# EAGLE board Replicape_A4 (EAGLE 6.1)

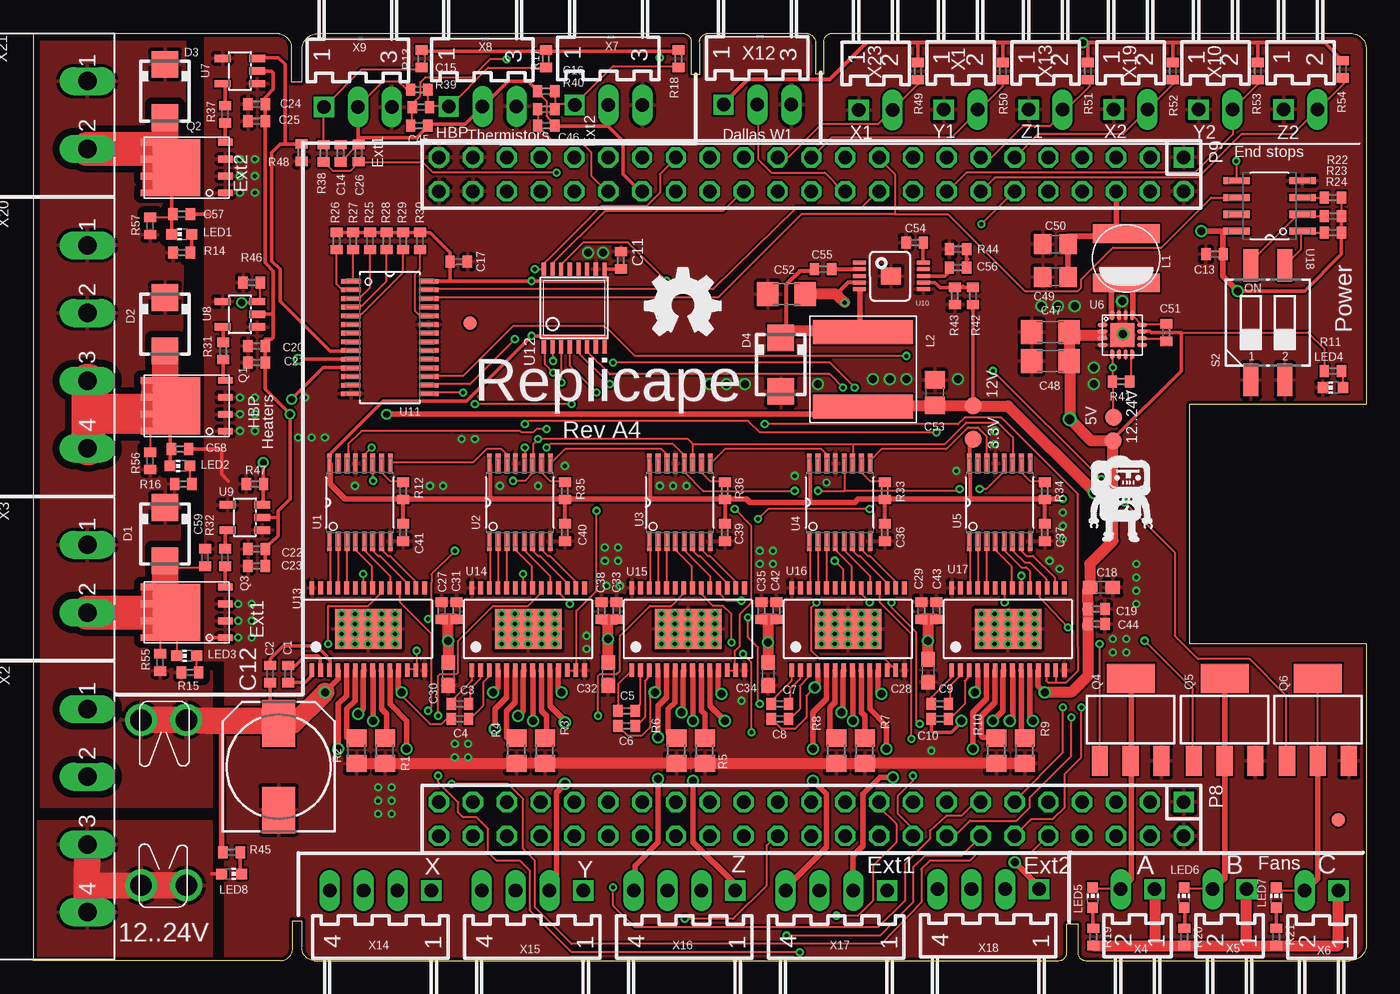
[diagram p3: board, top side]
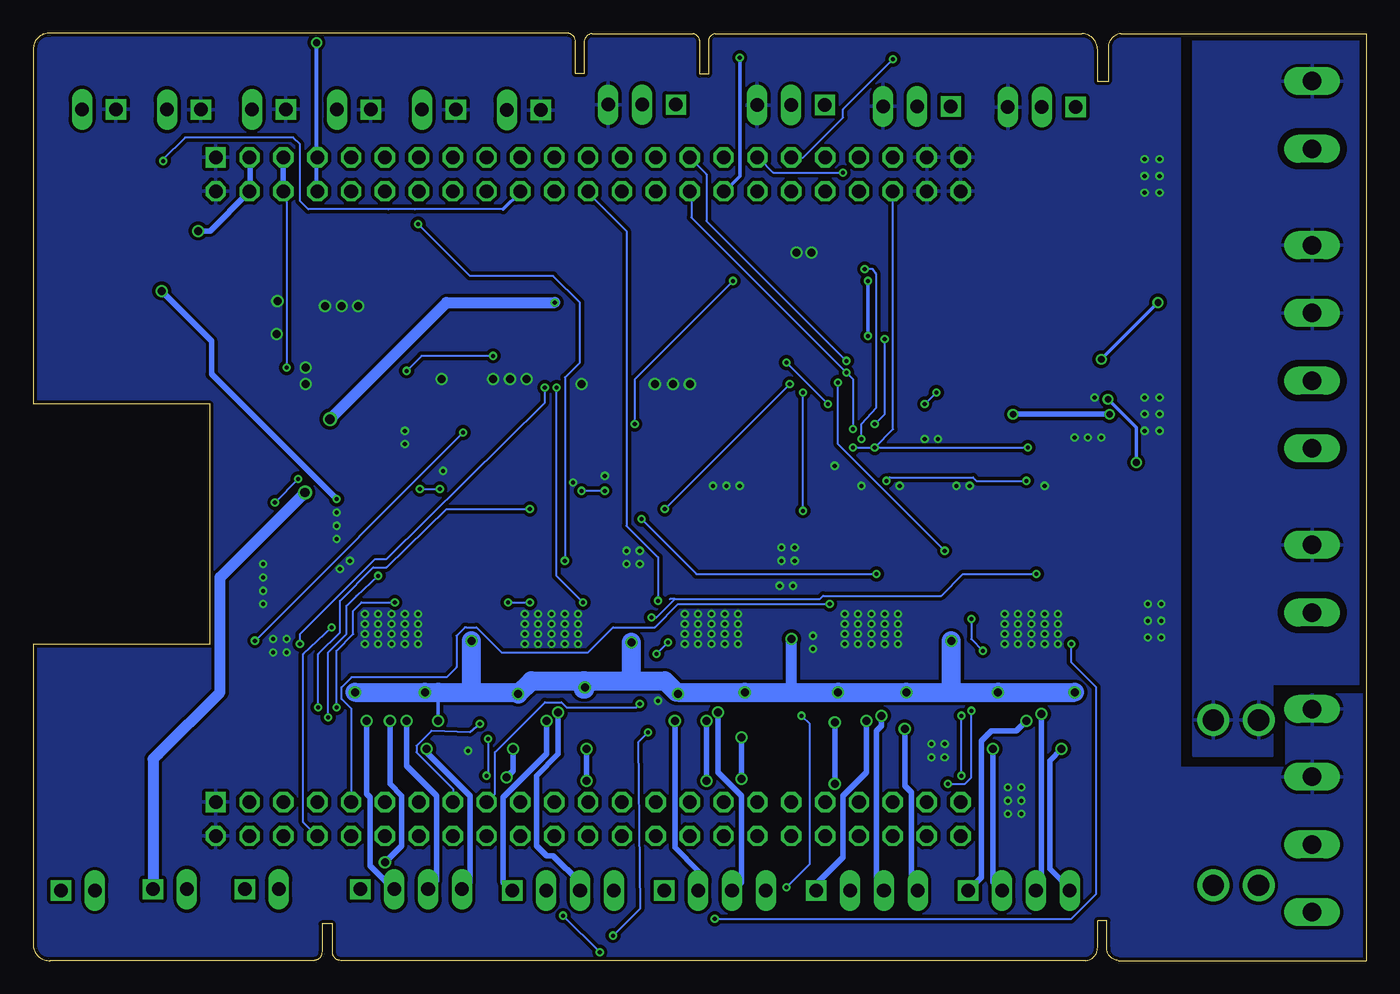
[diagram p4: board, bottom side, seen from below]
Size 100 x 69.58 mm. Coordinates in mm from the lower left corner, seen from the top.
Outline: 19.45,3 20.15,3 20.15,1.05 arc90 21.05,0 76.95,0 arc90 77.55,0.65 77.55,2.75 78.35,2.75 78.35,0.65 arc90 78.95,0 98.75,0 arc90 100,1.1 100,23.75 86.75,23.75 86.75,41.75 100,41.75 100,68.5 arc90 98.75,69.58 59.88,69.58 arc90 59.33,68.9 59.33,66.55 58.67,66.55 58.67,68.85 arc90 58.08,69.55 50.5,69.55 arc90 50,68.85 50,66.5 49.35,66.5 49.35,68.85 arc90 48.85,69.55 21.35,69.55 arc90 20.15,68.35 20.15,65.95 19.35,65.95 19.35,68.35 arc90 18.43,69.55 0,69.55 0,0 18.6,0 arc90 19.45,0.95 19.45,3
Copper layers (1*16): Top 0.035mm / dielectric 1.5mm / Bottom 0.035mm
Design rules: minimum track width 6mil, minimum drill 12mil, track to track 6mil, track to pad 6mil, pad to pad 6mil, via to via 6mil, smd to smd 0mil, copper to edge 10mil, drill to drill 10mil, minimum pad ring 10mil, minimum via ring 6mil, stop-mask expansion 2mil, vias tented up to drill 100mil, thermal gap 10mil
Net classes: 1 power: width 1.27 mm

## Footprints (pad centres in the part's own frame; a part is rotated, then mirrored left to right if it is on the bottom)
B1,27 = smd 1.27 x 1.27: TP 0,0
C0402 = smd 0.7 x 0.9: 1 -0.65,0; 2 0.65,0
140CLH-0810 = smd 3.5 x 2.5: + 3.25,0; - -3.25,0
C0603 = smd 1.1 x 1: 1 -0.85,0; 2 0.85,0
C1206 = smd 1.6 x 1.8: 1 -1.4,0; 2 1.4,0
C0805 = smd 1.3 x 1.5: 1 -0.95,0; 2 0.95,0
SMA = smd 2 x 2: A 2,0; C -2,0
3557 = drill 1.6: 1 -6.2,1.7; 2 -6.2,-1.7; 3 6.2,-1.7; 4 6.2,1.7
FIDUCIAL-1X2.5 = smd 1 x 1: 1 0,0
VLC5020 = smd 5 x 1.4: 1 0,1.85; 2 0,-1.85
NR8040T330 = smd 1.8 x 7.5: P$1 2.8,0; P$2 -2.8,0
CHIP-LED0603 = smd 0.8 x 0.8: A 0,-0.75; C 0,0.75
DIL-100-2X23 = drill 1.016 square: 1 -27.94,-1.27 | drill 1.016 octagon: 2 -27.94,1.27; 3 -25.4,-1.27; 4 -25.4,1.27; 5 -22.86,-1.27; 6 -22.86,1.27; 7 -20.32,-1.27; 8 -20.32,1.27; 9 -17.78,-1.27; 10 -17.78,1.27; 11 -15.24,-1.27; 12 -15.24,1.27; 13 -12.7,-1.27; 14 -12.7,1.27; 15 -10.16,-1.27; 16 -10.16,1.27; 17 -7.62,-1.27; 18 -7.62,1.27; 19 -5.08,-1.27; 20 -5.08,1.27; 21 -2.54,-1.27; 22 -2.54,1.27; 23 0,-1.27; 24 0,1.27; 25 2.54,-1.27; 26 2.54,1.27; 27 5.08,-1.27; 28 5.08,1.27; 29 7.62,-1.27; 30 7.62,1.27; 31 10.16,-1.27; 32 10.16,1.27; 33 12.7,-1.27; 34 12.7,1.27; 35 15.24,-1.27; 36 15.24,1.27; 37 17.78,-1.27; 38 17.78,1.27; 39 20.32,-1.27; 40 20.32,1.27; 41 22.86,-1.27; 42 22.86,1.27; 43 25.4,-1.27; 44 25.4,1.27; 45 27.94,-1.27; 46 27.94,1.27
8-DFN-EP-(5X6) = smd 1.1 x 0.5: 1 -2.9,1.905; 2 -2.9,0.635; 3 -2.9,-0.635; 4 -2.9,-1.905; 5 2.9,-1.905; 6 2.9,-0.635; 7 2.9,0.635; 8 2.9,1.905 | smd 3.5 x 4.3: TH 0.75,0
SOT223 = smd 1.219 x 2.235: 1 -2.311,-3.099; 2 0,-3.099; 3 2.311,-3.099 | smd 3.6 x 2.2: 4 0,3.099
R0805 = smd 1.3 x 1.5: 1 -0.95,0; 2 0.95,0
R0402 = smd 0.7 x 0.9: 1 -0.65,0; 2 0.65,0
CTS-219-02 = smd 1.13 x 2.44: 1 -1.27,-4.3; 2 1.27,-4.3; 3 1.27,4.3; 4 -1.27,4.3
SOP65P640X120-16N = smd 1.473 x 0.356: 1 -2.921,2.286; 2 -2.921,1.626; 3 -2.921,0.965; 4 -2.921,0.33; 5 -2.921,-0.33; 6 -2.921,-0.965; 7 -2.921,-1.626; 8 -2.921,-2.286; 9 2.921,-2.286; 10 2.921,-1.626; 11 2.921,-0.965; 12 2.921,-0.33; 13 2.921,0.33; 14 2.921,0.965; 15 2.921,1.626; 16 2.921,2.286
QFN-16 = smd 0.75 x 0.3: 1 -1.475,0.75; 2 -1.475,0.25; 3 -1.475,-0.25; 4 -1.475,-0.75; 9 1.475,-0.75; 10 1.475,-0.25; 11 1.475,0.25; 12 1.475,0.75 | smd 0.3 x 0.75: 5 -0.75,-1.475; 6 -0.25,-1.475; 7 0.25,-1.475; 8 0.75,-1.475; 13 0.75,1.475; 14 0.25,1.475; 15 -0.25,1.475; 16 -0.75,1.475 | smd 1.8 x 1.8: P$17 0,0
SOT23-5L = smd 0.55 x 1.2: 1 -0.95,-1.3; 2 0,-1.3; 3 0.95,-1.3; 4 0.95,1.3; 5 -0.95,1.3
MSOP10 = smd 0.3 x 1: 1 -1,-2.4; 2 -0.5,-2.4; 3 0.005,-2.4; 4 0.5,-2.4; 5 1,-2.4; 6 1,2.4; 7 0.5,2.4; 8 0.005,2.4; 9 -0.5,2.4; 10 -1,2.4 | smd 1.3 x 1.5: EP 0.02,-0.04
SOP65P640X110-28N = smd 1.473 x 0.356: 1 -2.921,4.216; 2 -2.921,3.581; 3 -2.921,2.921; 4 -2.921,2.286; 5 -2.921,1.626; 6 -2.921,0.965; 7 -2.921,0.33; 8 -2.921,-0.33; 9 -2.921,-0.965; 10 -2.921,-1.626; 11 -2.921,-2.286; 12 -2.921,-2.921; 13 -2.921,-3.581; 14 -2.921,-4.216; 15 2.921,-4.216; 16 2.921,-3.581; 17 2.921,-2.921; 18 2.921,-2.286; 19 2.921,-1.626; 20 2.921,-0.965; 21 2.921,-0.33; 22 2.921,0.33; 23 2.921,0.965; 24 2.921,1.626; 25 2.921,2.286; 26 2.921,2.921; 27 2.921,3.581; 28 2.921,4.216
TSSOP-16 = smd 0.305 x 0.991: 1 -2.275,-2.918; 2 -1.625,-2.918; 3 -0.975,-2.918; 4 -0.325,-2.918; 5 0.325,-2.918; 6 0.975,-2.918; 7 1.625,-2.918; 8 2.275,-2.918; 9 2.275,2.918; 10 1.625,2.918; 11 0.975,2.918; 12 0.325,2.918; 13 -0.325,2.918; 14 -0.975,2.918; 15 -1.625,2.918; 16 -2.275,2.918
TSSOP-28 = smd 0.35 x 1: 1 -4.225,-3.087; 2 -3.575,-3.087; 3 -2.925,-3.087; 4 -2.275,-3.087; 5 -1.625,-3.087; 6 -0.975,-3.087; 7 -0.325,-3.087; 8 0.325,-3.087; 9 0.975,-3.087; 10 1.625,-3.087; 11 2.275,-3.087; 12 2.925,-3.087; 13 3.575,-3.087; 14 4.225,-3.087; 15 4.225,3.087; 16 3.575,3.087; 17 2.925,3.087; 18 2.275,3.087; 19 1.625,3.087; 20 0.975,3.087; 21 0.325,3.087; 22 -0.325,3.087; 23 -0.975,3.087; 24 -1.625,3.087; 25 -2.275,3.087; 26 -2.925,3.087; 27 -3.575,3.087; 28 -4.225,3.087 | smd 5 x 3: EXP 0,0
SOIC127P600X175-8N = smd 1.981 x 0.533: 1 -2.464,1.905; 2 -2.464,0.635; 3 -2.464,-0.635; 4 -2.464,-1.905; 5 2.464,-1.905; 6 2.464,-0.635; 7 2.464,0.635; 8 2.464,1.905
7395-02 = drill 1.016 square: 1 1.27,0 | drill 1.016 long: 2 -1.27,0
MSTBA4 = drill 1.397 long: 1 -7.62,5.08; 2 -2.54,5.08; 3 2.54,5.08; 4 7.62,5.08
MSTBA2 = drill 1.397 long: 1 -2.54,5.08; 2 2.54,5.08
7395-03 = drill 1.016 square: 1 2.54,0 | drill 1.016 long: 2 0,0; 3 -2.54,0
7395-04 = drill 1.016 square: 1 3.81,0 | drill 1.016 long: 2 1.27,0; 3 -1.27,0; 4 -3.81,0

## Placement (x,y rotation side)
3.3V  TPB1,27  [B1,27]  70.5,39.13 0 top
5V  TPB1,27  [B1,27]  81.05,40.75 0 top
12..24V  TPB1,27  [B1,27]  81,39 0 top
12V  TPB1,27  [B1,27]  70.5,41.63 0 top
C1  10nF  [C0402]  19.12,21.5 270 top
C2  0.1uF  [C0402]  17.75,21.5 90 top
C3  10nF  [C0402]  32,19.25 180 top
C4  0.1uF  [C0402]  32,18.13 0 top
C5  10nF  [C0402]  44.5,18.75 180 top
C6  0.1uF  [C0402]  44.5,17.63 0 top
C7  10nF  [C0402]  56,19.25 180 top
C8  0.1uF  [C0402]  56,18.13 0 top
C9  10nF  [C0402]  68,19.25 180 top
C10  0.1uF  [C0402]  68,18.13 0 top
C11  0.1uF  [C0402]  44.08,52.55 90 top
C12  100uF  [140CLH-0810]  18.4,14.55 90 top
C13  0.1uF  [C0402]  88.62,53 180 top
C14  0.47uF  [C0402]  23.05,60.58 270 top
C15  0.47uF  [C0402]  28.95,65.35 180 top
C16  0.47uF  [C0402]  38.48,65.23 180 top
C17  0.1uF  [C0402]  31.92,52.43 0 top
C18  4.7uF  [C0603]  80.12,28 0 top
C19  0.1uF  [C0402]  79.75,26.38 0 top
C20  0.1uF  [C0402]  16.75,46.13 180 top
C21  4.7uF  [C0402]  16.75,44.88 180 top
C22  0.1uF  [C0402]  16.75,30.88 180 top
C23  4.7uF  [C0402]  16.75,29.63 180 top
C24  0.1uF  [C0402]  16.75,64.25 180 top
C25  4.7uF  [C0402]  16.75,63 180 top
C26  0.47uF  [C0402]  24.4,60.6 90 top
C27  0.1uF  [C0402]  30.62,26.25 90 top
C28  4.7uF  [C0603]  67.12,21.75 270 top
C29  0.1uF  [C0402]  66.62,26.25 90 top
C30  4.7uF  [C0603]  31.12,21.5 270 top
C31  0.1uF  [C0402]  31.75,26.25 90 top
C32  4.7uF  [C0603]  43.12,21.5 270 top
C33  0.1uF  [C0402]  43.75,26.25 90 top
C34  4.7uF  [C0603]  55.12,21.5 270 top
C35  0.1uF  [C0402]  54.62,26.25 90 top
C36  0.1uF  [C0402]  63.88,32.13 270 top
C37  0.1uF  [C0402]  75.88,32.13 270 top
C38  0.1uF  [C0402]  42.62,26.25 90 top
C39  0.1uF  [C0402]  51.88,32.13 270 top
C40  0.1uF  [C0402]  39.88,32.13 270 top
C41  0.1uF  [C0402]  27.75,32.13 270 top
C42  0.1uF  [C0402]  55.75,26.25 90 top
C43  0.1uF  [C0402]  67.75,26.25 90 top
C44  0.1uF  [C0402]  79.75,25.25 0 top
C45  0.47uF  [C0402]  28.95,62.65 0 top
C46  0.47uF  [C0402]  38.48,62.65 0 top
C47  10uF  [C1206]  76.3,47.18 180 top
C48  10uF  [C1206]  76.3,45 180 top
C49  22uF  [C0805]  76.67,51.3 180 top
C50  22uF  [C0805]  76.67,53.75 180 top
C51  22nF  [C0402]  85,47.13 90 top
C52  10uF  [C1206]  56.5,50 180 top
C53  22uF  [C0805]  67.62,42.63 90 top
C54  10nF  [C0402]  66.12,53.88 180 top
C55  10nF  [C0402]  59.25,51.88 180 top
C56  1nF  [C0402]  69.38,52 0 top
C57  4.7nF  [C0402]  11.12,56 0 top
C58  4.7nF  [C0402]  11,38.38 0 top
C59  4.7nF  [C0402]  12.88,30.25 90 top
D1  MBRA340T3  [SMA]  9.88,32 270 top
D2  MBRA340T3  [SMA]  9.88,47.75 270 top
D3  MBRA340T3  [SMA]  9.88,65.25 270 top
D4  MBRA340T3  [SMA]  56.08,44.73 270 top
F1  3557  [3557]  9.78,11.85 90 top
JP1  FIDUCIAL1X2.5  [FIDUCIAL-1X2.5]  32.77,47.83 0 top
JP2  FIDUCIAL1X2.5  [FIDUCIAL-1X2.5]  97.9,10.55 0 top
L1  4.7uH  [VLC5020]  82,52.7 180 top
L2  33uH  [NR8040T330]  62.25,44.38 270 top
LED1  blue  [CHIP-LED0603]  11.12,54.5 90 top
LED2  blue  [CHIP-LED0603]  11,37.13 90 top
LED3  blue  [CHIP-LED0603]  11.5,22.88 90 top
LED4  blue  [CHIP-LED0603]  97.5,43 90 top
LED5  blue  [CHIP-LED0603]  79.47,4.73 0 top
LED6  blue  [CHIP-LED0603]  86.33,4.73 0 top
LED7  blue  [CHIP-LED0603]  93.25,4.73 0 top
LED8  red  [CHIP-LED0603]  14.88,6.5 270 top
LOGO1  OSHW_LOGO_FILLX0200-NT  [OSHW_FILLX200_NOTEXT]  45.9,46.9 0 top
P8  F-2X23-  [DIL-100-2X23]  58.38,10.63 180 top
P9  F-2X23-  [DIL-100-2X23]  58.38,59 180 top
Q1  AON6758  [8-DFN-EP-(5X6)]  11.5,41.63 180 top
Q2  AON6758  [8-DFN-EP-(5X6)]  11.5,59.5 180 top
Q3  AON6758  [8-DFN-EP-(5X6)]  11.5,26.13 180 top
Q4  NIF5002  [SOT223]  82.33,18.08 0 top
Q5  NIF5002  [SOT223]  89.38,18.08 0 top
Q6  NIF5002  [SOT223]  96.38,18.08 0 top
R1  0.1R  [R0805]  26.38,15.75 90 top
R2  0.1R  [R0805]  24.25,15.75 90 top
R3  0.1R  [R0805]  38.38,15.75 90 top
R4  0.1R  [R0805]  36.25,15.75 90 top
R5  0.1R  [R0805]  50.38,15.75 90 top
R6  0.1R  [R0805]  48.25,15.75 90 top
R7  0.1R  [R0805]  62.38,15.75 90 top
R8  0.1R  [R0805]  60.25,15.75 90 top
R9  0.1R  [R0805]  74.38,15.75 90 top
R10  0.1R  [R0805]  72.25,15.75 90 top
R11  4.7K  [R0402]  97.5,44.25 180 top
R12  4.7K  [R0402]  27.75,35.25 270 top
R13  4K7, 1%  [R0402]  29.12,67.68 90 top
R14  4.7K  [R0402]  11.12,53.13 180 top
R15  4.7K  [R0402]  11.75,21.63 180 top
R16  4.7K  [R0402]  11.25,35.75 180 top
R17  4K7, 1%  [R0402]  38.45,67.68 90 top
R18  4K7, 1%  [R0402]  48.4,67.68 90 top
R19  4.7K  [R0402]  79.53,1.78 270 top
R20  4.7K  [R0402]  86.35,1.78 270 top
R21  4.7K  [R0402]  93.25,1.78 270 top
R22  4.7K  [R0402]  97.5,57.25 0 top
R23  4.7K  [R0402]  97.5,55.88 0 top
R24  4.7K  [R0402]  97.5,54.63 0 top
R25  4.7K  [R0402]  25.25,54 90 top
R26  4.7K  [R0402]  22.75,54 90 top
R27  4.7K  [R0402]  24,54 90 top
R28  4.7K  [R0402]  26.5,54 90 top
R29  4.7K  [R0402]  27.75,54 90 top
R30  4.7K  [R0402]  29,54 90 top
R31  100R  [R0402]  14.25,45.75 90 top
R32  100R  [R0402]  14.38,30.25 90 top
R33  4.7K  [R0402]  63.88,35.25 270 top
R34  4.7K  [R0402]  75.88,35.25 270 top
R35  4.7K  [R0402]  39.88,35.25 270 top
R36  4.7K  [R0402]  51.88,35.25 270 top
R37  100R  [R0402]  14.38,63.5 90 top
R38  6.8K  [R0402]  21.77,60.58 270 top
R39  6.8K  [R0402]  29.07,64.05 180 top
R40  6.8K  [R0402]  38.48,63.88 180 top
R41  10K  [R0402]  81.6,43.45 180 top
R42  120K  [R0402]  70.5,49.88 90 top
R43  10K  [R0402]  69.12,49.88 270 top
R44  40K  [R0402]  69.38,53.38 180 top
R45  4.7K  [R0402]  14.88,8.13 0 top
R46  4.7K  [R0402]  16.38,50.88 0 top
R47  4.7K  [R0402]  16.62,35.75 0 top
R48  4.7K  [R0402]  20.12,60.63 90 top
R49  1k  [R0402]  66.38,66.75 90 top
R50  1k  [R0402]  72.75,66.75 90 top
R51  1k  [R0402]  79.12,66.75 90 top
R52  1k  [R0402]  85.5,66.75 90 top
R53  1k  [R0402]  91.88,66.75 90 top
R54  1k  [R0402]  98.25,66.88 90 top
R55  4.7K  [R0402]  9.5,22.38 270 top
R56  4.7K  [R0402]  8.75,37.5 270 top
R57  4.7K  [R0402]  8.75,55.13 270 top
S2  219-02  [CTS-219-02]  92.62,47.88 0 top
U1  SN74AHC595PW  [SOP65P640X120-16N]  24.5,34.38 90 top
U2  SN74AHC595PW  [SOP65P640X120-16N]  36.5,34.38 90 top
U3  SN74AHC595PW  [SOP65P640X120-16N]  48.5,34.38 90 top
U4  SN74AHC595PW  [SOP65P640X120-16N]  60.5,34.38 90 top
U5  SN74AHC595PW  [SOP65P640X120-16N]  72.5,34.38 90 top
U6  MCP16321  [QFN-16]  81.7,46.95 0 top
U7  MCP1402  [SOT23-5L]  15.5,66.75 90 top
U8  MCP1402  [SOT23-5L]  15.5,48.5 90 top
U9  MCP1402  [SOT23-5L]  15.88,33.25 90 top
U10  RT8268  [MSOP10]  64.38,51.38 270 top
U11  PCA9685PW  [SOP65P640X110-28N]  26.75,46.75 0 top
U12  DAC088S085  [TSSOP-16]  40.58,48.98 0 top
U13  DRV8825PWP  [TSSOP-28]  25.12,24.88 0 top
U14  DRV8825PWP  [TSSOP-28]  37.12,24.88 0 top
U15  DRV8825PWP  [TSSOP-28]  49.12,24.88 0 top
U16  DRV8825PWP  [TSSOP-28]  61.12,24.88 0 top
U17  DRV8825PWP  [TSSOP-28]  73.12,24.88 0 top
U18  CAT24C256  [SOIC127P600X175-8N]  92.75,56.63 180 top
U$1  [LOGO_BIG]  81.15,34.73 0 top
X1  22-05-7028-02  [7395-02]  69.58,63.85 180 top
X2  MSTBA4  [MSTBA4]  -1.02,11.25 270 top
X3  MSTBA2  [MSTBA2]  -1.02,28.65 270 top
X4  22-05-7028-02  [7395-02]  82.85,5.35 0 top
X5  22-05-7028-02  [7395-02]  89.75,5.35 0 top
X6  22-05-7028-02  [7395-02]  96.65,5.25 0 top
X7  22-05-7038-03  [7395-03]  43.15,64.2 180 top
X8  22-05-7038-03  [7395-03]  33.7,64.1 180 top
X9  22-05-7038-03  [7395-03]  24.35,64.05 180 top
X10  22-05-7028-02  [7395-02]  88.7,63.85 180 top
X11  22-05-7028-02  [7395-02]  95.08,63.88 180 top
X12  22-05-7038-03  [7395-03]  54.33,64.23 180 top
X13  22-05-7028-02  [7395-02]  75.95,63.85 180 top
X14  22-05-7048-04  [7395-04]  26.05,5.25 0 top
X15  22-05-7048-04  [7395-04]  37.45,5.25 0 top
X16  22-05-7048-04  [7395-04]  48.85,5.25 0 top
X17  22-05-7048-04  [7395-04]  60.25,5.25 0 top
X18  22-05-7048-04  [7395-04]  71.65,5.35 0 top
X19  22-05-7028-02  [7395-02]  82.33,63.88 180 top
X20  MSTBA4  [MSTBA4]  -1.02,46.05 270 top
X21  MSTBA2  [MSTBA2]  -1.02,63.45 270 top
X23  22-05-7028-02  [7395-02]  63.2,63.83 180 top

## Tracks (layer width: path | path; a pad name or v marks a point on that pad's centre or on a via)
+3V3  (via drill 0.3, 0.6)
  Top 0.152: R23.2 R22.2 | 22.25,38 22.25,37.38 U1.16 | v37.38,51 37.25,51 | 75.88,34.63 R34.2
  Top 0.254: 89.25,54.63 89.38,54.75 90.25,54.75 U18.8 | 89.25,53 C13.1 89.25,52.88 | v90.38,50.25 95.38,50.25 98.12,53 98.12,54.63 R24.2 98.12,54.75 98.12,55.88 R23.2 | 31.25,51 29.75,51 U11.28 | 31.25,51 31.25,52.38 31.38,52.5 31.25,52.63 C17.1 31.25,52.5 31.25,53.13 29.75,54.63 29,54.63 R30.2 28.88,54.63 27.75,54.63 R29.2 27.62,54.63 26.5,54.63 R28.2 26.38,54.63 25.25,54.63 R25.2 25,54.63 24,54.63 R27.2 23.88,54.63 22.75,54.63 R26.2 | 31.25,51 37.25,51 42.88,51 42.88,51.88 U12.9 43,51.88 44,51.88 C11.1 | 42.25,46.88 42.25,46.13 U12.7 | 42.25,46.88 42.88,46.88 42.88,46.13 U12.8 | 42.25,46.88 v37.38,46.88 32.5,42 26.25,42 22.25,38
  Top 0.305: 89.25,54.75 89.25,54.63 | C36.1 R33.2 | C37.1 R34.2 75.75,34.63 | 64,34.63 R33.2 | 70.25,34.63 70.25,37.25 U5.16 70.25,37.38 70.25,38.88 3.3V.TP | 58.25,34.38 58.25,37.25 U4.16 | 63.75,34.63 R33.2 | 51.88,34.63 R36.2 | R36.2 C39.1 | C40.1 R35.2 | 40,34.63 R35.2 | 46.25,34.63 46.25,37.25 U3.16 | 51.75,34.63 R36.2 | C41.1 R12.2 | 27.88,34.63 R12.2 | 34.25,34.63 34.25,37.25 U2.16 | 39.75,34.63 R35.2 | 27.62,34.63 R12.2 | 22.25,37.25 U1.16
  Top 0.406: 89.25,53 89.25,54.63 | v90.38,50.25 89.25,51.38 89.25,52.88 | 89.25,54.75 v87.62,54.75 | 64,34.63 70.25,34.63 75.75,34.63 | 63.75,34.63 61.88,34.63 61.62,34.38 58.25,34.38 53.75,34.38 53.5,34.63 51.88,34.63 | 40,34.63 46.25,34.63 51.75,34.63 | 27.88,34.63 34.25,34.63 39.75,34.63 | 27.62,34.63 23.38,34.63 22.25,35.75 22.25,37.25 | 75.88,34.63 v77.25,34.63
  Bottom 0.152: P9.4 83.88,57.75 83.81,57.66 | 83.75,60.13 83.75,60.25 P9.3
  Bottom 0.254: v37.38,46.88 v37.38,51
  Bottom 0.305: 83.88,57.63 83.81,57.66
  Bottom 0.406: 83.81,60.2 83.75,60.13 83.75,57.75 83.81,57.66 | v87.62,54.75 86.75,54.75 83.88,57.63 | v77.25,34.63 86.62,44 86.62,46.5 v90.38,50.25
AGND
  Top 0.152: 29.62,62.75 C45.2 | C14.2 24.38,61.25 C26.2 | C15.2 28.25,65.38 28,65.38 27.38,66 26.25,66 24.38,64.13 X9.2 24.38,64 | 37.88,65.13 38.5,64.5 38.5,63.38 39.12,62.63 C46.2 | 43.12,64.13 X7.2 | 33.75,64.13 X8.2 | 37.88,65.25 C16.2 | P9.34 45.62,57.75 45.5,57.75
  Top 0.254: 29.62,62.75 32.38,62.75 33.62,64 X8.2 | 24.38,64 24.38,61.75 | 24.38,61.75 24.38,61.25 | 24.38,61.75 28.75,61.75 29.62,62.63 C45.2 | 37.88,65.13 C16.2 | 43.12,62.63 39.12,62.63 | 43.12,64.13 43.12,62.63 | 43.12,62.63 44.25,61.5 44.25,59 45.5,57.75 45.59,57.66 | 33.75,64.13 35.62,66 37.12,66 37.88,65.25
DALLAS_W1
  Top 0.152: X12.2 54.38,64.13 54.38,60.13 55.38,59.13 59.38,59.13 60.75,57.75 60.83,57.66 60.88,57.63 P9.22
DIR_EXT1  (via drill 0.3)
  Top 0.152: v62.75,26.88 62.12,27.5 62.12,27.88 U16.20 | v64.38,26.88 64.38,26.5 66.25,24.63 66.25,18 v66.5,17.75
  Bottom 0.152: v64.38,26.88 v62.75,26.88 | 68.5,12 68.5,12.88 71.25,15.63 71.25,16.13 70.12,17.25 67.25,17.13 v66.5,17.75 | 68.5,12 68.45,11.94 | 68.5,12 P8.15
DIR_EXT2  (via drill 0.3)
  Top 0.152: v74.12,28.88 74.12,27.88 U17.20 | v77.88,18.25 77.88,15.38 74.75,12.25 74.75,11.5 73.75,10.5 70.25,10.5 69.12,9.38 68.62,9.38 P8.16
  Bottom 0.152: v74.12,28.88 75.75,27.38 76.5,26.63 76.5,24.5 77.88,23.13 v77.88,18.25
DIR_X  (via drill 0.3)
  Top 0.152: v48.88,3.13 52.5,3.13 55,5.63 55,8.63 55.75,9.38 | U13.20 26,27.88 26,27.5 25.12,26.63 22.12,26.63 v22.12,23.75 | 55.75,9.38 55.75,9.4 | 55.75,9.38 P8.26
  Bottom 0.152: v48.88,3.13 32.62,3.13 22.12,3.13 20.25,5 20.25,20.5 22.12,22.38 v22.12,23.75
DIR_Y  (via drill 0.3)
  Top 0.152: v30.38,18.38 30.38,21.38 30.5,21.5 31.75,21.5 31.88,21.63 31.88,24 34.5,26.63 37.12,26.63 38,27.5 38,27.88 U14.20 | v30.38,13.88 30.38,13.38 31.88,11.88 31.88,11.13 32.25,10.75 33.25,10.75 34.12,9.88 34.12,8.13 34.75,7.5 36.5,7.5 37.25,6.75 37.25,3.75 40.38,0.63 v57.5,0.63 | v60.25,3.38 61.88,3.38 63,4.5 63,7.13 64.75,8.88 64.75,10.25 63.38,11.63 | 63.38,11.63 63.37,11.94 | 63.38,11.63 P8.19
  Bottom 0.152: v30.38,13.88 v30.38,18.38 | v60.25,3.38 v57.5,0.63
DIR_Z  (via drill 0.3)
  Top 0.152: v52.38,23.88 52.38,26 51.75,26.63 51,26.63 50.12,27.5 50.12,27.88 U15.20 | v53.25,23 53.88,22.38 v53.88,17.13 | v56.5,1.88 63.5,1.88 66,4.38 66,7 66.88,7.88 69.62,7.88 71,9.25 P8.14
  Bottom 0.152: v53.25,23 v52.38,23.88 | v53.88,17.13 54.62,16.38 54.5,3.88 v56.5,1.88
END_STOP_X_1
  Top 0.152: 55.88,60.25 56.62,60.25 59.12,62.75 63.38,62.75 64.38,63.75 X23.2 64.5,63.88 66.38,65.75 66.38,66 R49.1 | 55.88,60.25 55.75,60.25 55.75,60.2 | 55.88,60.25 P9.25
END_STOP_X_2
  Top 0.152: 83.62,63.88 81.75,62 75.38,62 73.62,60.25 P9.11 | 83.62,63.88 X19.2 83.62,63.88 | 83.62,63.88 85.5,65.75 85.75,66 R52.1
END_STOP_Y_1
  Top 0.152: 58.38,60.25 59.88,61.75 68.88,61.75 70.88,63.75 X1.2 71,63.88 72.75,65.63 72.75,66 R50.1 | 58.38,60.25 58.29,60.2 | 58.38,60.25 P9.23
END_STOP_Y_2
  Top 0.152: 68.62,57.75 70,59.13 87.12,59.13 90,62 90,63.38 X10.2 90,63.88 91.88,65.75 92.12,66 R53.1 | 68.62,57.75 68.45,57.66 | 68.62,57.75 P9.16
END_STOP_Z_1
  Top 0.152: P9.13 71.12,60.25 71.88,60.25 74.25,62.63 76.25,62.63 77.38,63.75 X13.2 77.5,63.88 79.25,65.63 79.25,66 R51.1
END_STOP_Z_2
  Top 0.152: 71.12,57.75 72.12,58.75 87.38,58.75 88,59.38 | 71.12,57.75 70.99,57.66 | 71.12,57.75 P9.14 | R54.1 98.62,66.13 98.5,66 96.62,64.13 X11.2
  Top 0.154: 88,59.38 90.62,62 94.5,62 96.38,63.88
  Top 0.254: 96.38,63.88 X11.2
EXT1_DECAY
  Top 0.152: U16.19 62.75,28.88 60.88,30.75 60.88,31.38 U4.5
EXT1_MODE0
  Top 0.152: U16.24 59.5,31.38 U4.3
EXT1_MODE1
  Top 0.152: U16.25 58.88,28 58.88,31.38 U4.2
EXT1_MODE2
  Top 0.152: U16.26 58.25,28 58.25,31.38 U4.1
EXT1_NENABLE
  Top 0.152: U16.21 61.38,28 61.38,29.63 60.25,30.75 60.25,31.38 U4.4
EXT1_NRESET
  Top 0.152: U16.16 64.62,28 64.62,28.5 62.75,30.38 62.62,30.38 62.25,30.75 62.25,31.38 U4.7
EXT1_NSLEEP
  Top 0.152: U16.17 64,28 64,28.38 62,30.38 61.88,30.38 61.5,30.75 61.5,31.38 U4.6
EXT2_DECAY
  Top 0.152: U17.19 74.75,29.25 74.5,29.5 74.12,29.5 72.88,30.75 72.88,31.38 U5.5
EXT2_MODE0
  Top 0.152: U17.24 71.5,31.38 U5.3
EXT2_MODE1
  Top 0.152: U17.25 70.88,28 70.88,31.38 U5.2
EXT2_MODE2
  Top 0.152: U17.26 70.25,28 70.25,31.38 U5.1
EXT2_NENABLE
  Top 0.152: U17.21 73.38,28 73.38,29.63 72.25,30.75 72.25,31.38 U5.4
EXT2_NRESET
  Top 0.152: U17.16 76.62,28 76.62,28.75 75,30.38 74.5,30.38 74.12,30.75 74.12,31.38 U5.7
EXT2_NSLEEP
  Top 0.152: U17.17 76,28 76,28.63 74.75,29.88 74.38,29.88 73.5,30.75 73.5,31.38 U5.6
FAN_1  (via drill 0.3)
  Top 0.152: v32.25,42.63 29.75,42.63 U11.15 | v40.38,41.75 v33.12,41.75 | v43.5,44.88 59.75,44.88 v61.62,43 | v80,23.75 80,15 Q4.1
  Bottom 0.152: v33.12,41.75 v32.25,42.63 | v43.5,44.88 v40.38,41.75 | v61.62,43 61.62,41.88 73.5,30.13 74.38,30.13 80,24.5 v80,23.75
FAN_2  (via drill 0.3)
  Top 0.152: v36.12,46.63 32.75,43.25 29.75,43.25 U11.16 | v36.88,40.25 37.12,40.5 53.62,40.5 54.5,39.63 v67.75,39.63 | v83.38,24 87,20.38 87,15 Q5.1
  Bottom 0.152: v36.12,46.63 36.12,41 v36.88,40.25 | v83.38,24 v67.75,39.63
FAN_3  (via drill 0.3)
  Top 0.152: v65.5,45.38 45.12,45.38 43.12,47.38 42.75,47.63 36,47.63 32.25,43.88 29.75,43.88 U11.17 | v80.12,36.13 v72,44.25 | Q6.1 94,15 94,19.88 91.25,22.63 87.38,22.63 85.62,24.38 85.62,30.63 v81.88,34.38
  Bottom 0.152: v80.12,36.13 v81.88,34.38
  Bottom 0.154: v72,44.25 70.88,45.38 v65.5,45.38
FAULT_EXT1  (via drill 0.3)
  Top 0.152: v65.88,16.63 65.88,24.5 63.5,26.88 63.5,27.88 U16.18 | v66,13.88 66,13.5 64.88,12.38 64.88,11 65.88,10 65.88,9.38 P8.18
  Bottom 0.152: v65.88,16.63 65.88,14 v66,13.88
FAULT_EXT2  (via drill 0.3)
  Top 0.152: v77.62,25 75.5,27.25 75.5,27.88 U17.18
  Bottom 0.152: v77.62,25 79.75,23 79.75,10.38 78.75,9.38 P8.8
FAULT_X  (via drill 0.3)
  Top 0.152: v29.62,18.75 29.88,19 29.88,24.5 27.5,26.88 27.5,27.88 U13.18 | v31.38,13.25 35.62,13.25 36.75,12.13 36.75,8.38 37.62,7.5 37.62,4 40.38,1.25 63.62,1.25 66.62,4.38 66.62,6.88 67.25,7.5 70.25,7.5 70.88,8.13 74.88,8.13 76,9.25 76.12,9.25 P8.10
  Bottom 0.152: v29.62,18.75 29.62,13.75 30.12,13.25 v31.38,13.25
FAULT_Y  (via drill 0.3)
  Top 0.152: v40.25,26.75 39.5,27.5 39.5,27.88 U14.18
  Bottom 0.152: v40.25,26.75 51.62,26.75 53.38,25 56.5,25 58.38,23.13 64.88,23.13 66.75,25 67.5,25 67.62,25 68.25,24.38 68.25,22 69,21.25 76.12,21.25 76.88,20.5 76.88,19.63 76.12,18.88 76.12,12 P8.9
FAULT_Z  (via drill 0.3)
  Top 0.152: v53.12,27 52,27 51.5,27.5 51.5,27.88 U15.18
  Bottom 0.152: v53.12,27 53.12,30.25 55.5,32.63 55.5,54.75 58.38,57.63 | 58.38,57.63 58.29,57.66 | 58.38,57.63 P9.24
GND  (via drill 0.3, 0.6)
  Top 0.152: 54.62,27 C35.2 | 80.25,46.25 U6.4 80.25,46.25
  Top 0.254: 14.62,36 14.12,36.5 14.12,38.38 C58.2 | 13.38,56 C57.2 | 14.5,24.25 13.12,24.25
  Top 0.819: R2.1 R4.1 R3.1 R5.1 R8.1 R7.1 R9.1 R10.1 | R6.1 49.38,14.8
  other vias: 16.38,24.25 15.38,24.25 15.38,25.5 16.38,25.5 15.38,26.75 16.38,26.75 15.5,60.13 16.62,60.13 15.5,58.88 16.62,58.88 15.5,57.63 16.62,57.63 16.62,39.75 15.5,39.75 15.5,41 16.62,41 15.5,42.25 16.62,42.25 81.75,47 81.69,49.5 79.56,44.5 79.56,43.25 20.38,42.25 75.62,49.13 76.88,49.13 78.12,49.13 65.5,43.63 64.25,43.63 63,43.63 69.38,43.63 41.62,53.13 42.75,53.13 31.62,16.25 32.62,16.25 32.62,15.25 31.62,15.25 25.88,13 26.88,13 26.88,12 25.88,12 37.12,24.5 37.12,25.25 37.12,26 37.12,23.75 23.12,23.75 27.12,23.75 27.12,26 23.12,26 41.5,24.38 41.5,23.38 43,28.13 44,28.13 43.88,30 42.88,30 42.88,31 43.88,31 54.5,30.75 55.5,30.75 55.5,29.75 54.5,29.75 53.12,19.5 47.12,23.75 51.12,23.75 51.12,26 47.12,26 59.12,23.75 63.12,23.75 63.12,26 59.12,26 72.12,26 71.12,23.75 71.12,26 81,23.13 82,23.13 82.75,27.75 82.75,28.75 76.25,30 77,29.38 77.25,31.63 77.25,32.63 77.25,33.63 21.88,39.25 20.88,39.25 19.88,39.25 24.12,35.63 29.75,35.63 30.75,35.63 72.12,38.75 72.12,39.75 47,35.63 48,35.63 49,35.63 59.5,35.88 58.88,43.25 53.38,43.25 52,43.25 50.75,43.25 25.88,11 26.88,11 71.12,25.25 71.12,24.5 72.12,25.25 74.12,25.25 73.12,25.25 72.12,24.5 74.12,24.5 73.12,24.5 75.12,24.5 72.12,23.75 74.12,23.75 73.12,23.75 59.12,25.25 59.12,24.5 60.12,26 61.12,26 60.12,25.25 62.12,26 61.12,25.25 62.12,25.25 63.12,25.25 63.12,24.5 62.12,24.5 61.12,24.5 60.12,24.5 60.12,23.75 61.12,23.75 62.12,23.75 75.12,23.75 73.12,26 49.12,26 48.12,26 49.12,23.75 50.12,23.75 48.12,23.75 50.12,26 47.12,25.25 47.12,24.5 48.12,24.5 48.12,25.25 49.12,25.25 49.12,24.5 50.12,24.5 50.12,25.25 51.12,25.25 51.12,24.5 35.12,26 35.12,23.75 39.12,23.75 39.12,26 36.12,26 36.12,25.25 35.12,25.25 35.12,24.5 36.12,24.5 36.12,23.75 38.12,23.75 38.12,24.5 38.12,25.25 38.12,26 39.12,25.25 39.12,24.5 25.12,26 25.12,23.75 25.12,24.5 25.12,25.25 24.12,26 24.12,25.25 24.12,24.5 24.12,23.75 23.12,24.5 23.12,25.25 26.12,26 26.12,25.25 26.12,24.5 26.12,23.75 27.12,24.5 27.12,25.25 82.75,26.75 82.75,29.75 74.12,26 75.12,25.25 75.12,26 81,24.13 82,24.13 67.38,15.75 57.12,36.38 69.25,36.75 35,35.63 37.88,35.63 39.88,37.13 33.12,39.13 32.12,39.13
  pour Top: 12.88,69.5 98.75,69.58 arc-90 100,68.5 100,41.75 86.75,41.75 86.75,23.63 100,23.63 100,1.25 arc-90 98.75,0 14.38,0 14.38,22.5 12.88,22.5
  pour Bottom (isolate 0.254): 98.75,69.58 14,69.5 14,14.5 6,14.5 6,20 0,20 0,0 98.75,0 arc90 100,1.25 100,23.63 86.75,23.63 86.75,41.75 100,41.75 100,68.5 arc90
HEATER_EXT1  (via drill 0.5)
  Top 0.152: 17.38,34.25 U9.3 17.12,34.25 | 17.25,35.63 R47.2 | 23.25,44.5 23.62,44.5 U11.11 | 17.12,34.5 17.25,34.5
  Top 0.254: 17.25,34.25 17.12,34.25 U9.3 | 17.25,34.13 U9.3 | 17.25,35.75 R47.2 | 17.25,35.88 R47.2 | 23.75,44.5 U11.11 23.25,44.5 21.75,44.5 v19.38,42.13 | 17.25,35.63 17.25,34.5 17.25,34.38 U9.3 | v17.25,37.38 17.25,36 R47.2
  Bottom 0.254: v19.38,42.13 17.25,40 v17.25,37.38
HEATER_EXT2
  Top 0.254: 23.75,45.75 U11.9 23.62,45.75 22.25,45.75 18.5,49.5 18.5,51.88 17.88,52.5 17.88,60.63 18.5,61.25 18.88,61.25 19,61.25 | 19,61.25 18.88,61.38 18.88,67.25 18.38,67.75 16.88,67.75 U7.3 | 19,61.25 20.12,61.25 R48.2
HEATER_HBP  (via drill 0.5)
  Top 0.152: R46.2 17,50.75 17,49.63 16.88,49.5 U8.3 16.75,49.38 | 23.62,45.13 U11.10
  Top 0.254: 17.12,51 R46.2 | 23.75,45.13 U11.10 | v15.62,49.38 16.75,49.38 | 23.62,45.13 v19.88,45.13
  Bottom 0.254: v19.88,45.13 v15.62,49.38
I2C2_SCL
  Top 0.152: 64.62,56 57.62,56 51.38,49.75 29.75,49.75 U11.26 | 64.62,56 64.62,59 63.38,60.25 P9.19 | 64.62,56 68.62,56 74.38,50.25 78.38,50.25 78.62,50.5 78.62,51.13 81,53.5 84.62,53.5 88.38,57.25 90.25,57.25 U18.6
I2C2_SDA  (via drill 0.3)
  Top 0.152: U11.27 29.75,50.38 51,50.38 57.25,56.5 62.12,56.5 63.25,57.63 63.37,57.66 63.38,57.75 P9.20 | U18.5 90.38,58.63 U18.5 | v90.25,60 90.25,58.63 U18.5
  Bottom 0.152: 64.75,56.38 71.38,56.38 73.38,56.38 79.38,56.38 80,57 80,61.25 80.5,61.75 88.62,61.75 90.25,60.13 v90.25,60
  Bottom 0.254: P9.20 63.45,57.67 64.75,56.38
N$8
  Top 0.254: LED8.C 15.5,6.63 R45.2
N$9
  Top 0.254: LED5.A 79.5,3.88 79.5,2.63 79.38,2.5 R19.1
N$16
  Top 0.254: U13.2 21.5,21.88 21.5,22.75 21.38,22.88 20.38,22.88 19.62,22.13 19,22.13 C1.1
N$17
  Top 0.254: U13.1 20.88,21.75 20.88,21.5 U13.1 | C1.2 19.12,20.88 20.38,20.88 20.88,21.38 U13.1
N$18
  Top 0.41: U13.9 26.12,21.75 26.12,18.88 26.5,18.5 26.5,16.75 26.38,16.75 R1.2
N$19
  Top 0.41: U13.6 24.12,21.75 24.12,19.5 23.5,18.88 23.5,16.75 24.25,16.75 R2.2
N$21
  Top 0.152: 14.38,32.13 14.5,32.13 14.5,32.25 U9.5
  Top 0.254: R32.2 14.38,31 14.38,31.75 14.38,32.13
N$22
  Top 0.254: U13.3 22.25,21.88 22.25,22.63 22.12,22.63 22,22.75 22,22.88 21.25,23.63 18.75,23.63 17.75,22.63 17.75,22.5 C2.2
N$23
  Top 0.254: Q2.4 14.38,61.5 14.38,61.88 14.38,62.75 R37.1
N$34
  Top 0.152: C3.1 32.75,19.25 32.75,20.38 33.5,21.13 33.5,21.75 U14.2
N$35
  Top 0.152: C3.2 31.38,19.25 31.38,19.5 32.88,21 32.88,21.75 U14.1
N$36
  Top 0.41: U14.9 38.12,21.75 38.12,18.75 38.5,18.38 38.5,16.75 38.38,16.75 R3.2
N$37
  Top 0.41: U14.6 36.12,21.75 36.12,19.38 35.5,18.75 35.5,16.75 36.25,16.75 R4.2
N$38
  Top 0.152: C4.2 32.75,18.13 33.75,19.13 33.75,20.88 34.12,21.25 34.12,21.75 U14.3
N$41
  Top 0.152: U7.5 14.5,65.63 14.38,65.63
  Top 0.254: R37.2 14.38,65.63
N$52
  Top 0.152: C5.1 45.5,19.25 45.5,21.75 U15.2
N$53
  Top 0.152: C5.2 43.88,18.75 43.88,20.75 44.88,21.75 U15.1
N$54
  Top 0.41: U15.9 50.12,21.75 50.12,18.75 50.38,18.5 50.38,17 50.12,16.75 50.38,16.75 R5.2
N$55
  Top 0.41: 48.25,16.75 R6.2 47.75,16.75 47.62,17.13 47.62,18.88 48.12,19.38 48.12,21.75 U15.6
N$56
  Top 0.152: C6.2 45.25,17.63 45.88,18.25 45.88,21 46.12,21.25 46.12,21.75 U15.3
N$58
  Top 0.152: R27.1 24,51.13 23.88,51 U11.1
N$59
  Top 0.152: R26.1 22.75,50.75 23.12,50.38 23.75,50.38 U11.2
N$60
  Top 0.254: Q1.4 14.25,43.63 14.25,44.13 14.25,45.13 14.38,45.13 R31.1
N$61
  Top 0.152: 14.25,47.5 U8.5
  Top 0.254: 14.25,47.5 R31.2
N$64
  Top 0.152: R57.1 8.75,55.75 10.25,55.75 C57.1
  Top 0.254: 10.38,56 LED1.C | 10.38,56 C57.1 | 10.38,56 10.38,57.63 9,57.63 8.62,57.63 Q2.8 8.5,57.5 8.62,57.75 | Q2.6 8.5,60.25 8.5,60.91 8.5,61.38 Q2.5 | 9.88,60.75 10.75,60.25 Q2.TH 10.75,59.38 10.75,58.88 8.62,58.88 Q2.7 8.5,58.75 8.5,58.63 8.62,59.88
  Top 0.813: 8.62,57.75 8.62,59.88
  Top 2: D3.A 9.88,60.75 9.75,60.88 9.62,60.91
  Top 2.54: X21.2 8.5,60.91 9.62,60.91
N$70
  Top 0.152: C7.1 56.75,19.25 56.75,20.38 57.5,21.13 57.5,21.75 U16.2
N$71
  Top 0.152: C7.2 55.38,19.25 55.38,19.5 56.88,21 56.88,21.75 U16.1
N$72
  Top 0.41: U16.9 62.12,21.75 62.12,18.63 62.38,18.38 62.38,16.88 62.25,16.75 62.38,16.63 R7.2
N$73
  Top 0.41: U16.6 60.12,21.75 60.12,19.38 59.75,19 59.75,16.75 60.25,16.75 R8.2
N$74
  Top 0.152: C8.2 56.75,18.13 57.5,18.88 57.5,20.63 58.12,21.25 58.12,21.75 U16.3
N$76
  Top 0.152: R25.1 25.25,50.5 24.5,49.75 23.88,49.75 U11.3
N$88
  Top 0.152: C9.1 68.75,19.25 68.75,20.63 69.5,21.38 69.5,21.75 U17.2
N$89
  Top 0.152: C9.2 67.38,19.25 67.38,19.75 68.88,21.25 68.88,21.75 U17.1
N$90
  Top 0.41: U17.9 74.12,21.75 74.12,16.75 74.38,16.75 R9.2
N$91
  Top 0.41: U17.6 72.12,21.75 72.12,19.38 71.12,18.38 71.12,16.88 71.25,16.75 72.25,16.75 R10.2
N$92
  Top 0.152: C10.2 68.75,18.13 69.88,19.25 69.88,21 70.12,21.25 70.12,21.75 U17.3
N$94
  Top 0.152: R28.1 26.5,51 24.62,49.13 23.88,49.13 U11.4
N$95
  Top 0.152: R29.1 27.75,51.63 24.62,48.5 23.88,48.5 U11.5
N$96
  Top 0.152: LED4.A 98.25,44.25 R11.1
N$97
  Top 0.152: R12.1 27.75,36 26.75,36 26.25,36.5 26.25,37.25 U1.10
N$98
  Top 0.152: R33.1 63.88,36 62.75,36 62.25,36.5 62.25,37.25 U4.10
N$99
  Top 0.152: R34.1 75.88,36 74.75,36 74.25,36.5 74.25,37.25 U5.10
N$100
  Top 0.152: R35.1 39.88,36 38.75,36 38.25,36.5 38.25,37.25 U2.10
N$101
  Top 0.152: R36.1 51.88,36 50.75,36 50.25,36.5 50.25,37.25 U3.10
N$112
  Top 0.152: R30.1 29,51.88 28.62,51.5 28.62,48.75 28.88,48.5 29.62,48.5 U11.24
N$114
  Top 0.152: X6.2 93.25,5.25 LED7.C | Q6.2 Q6.4
  Top 0.41: Q6.2 96.38,6.13 95.5,5.25 X6.2
N$115
  Top 0.152: LED6.C 86.5,5.38 88.38,5.38 X5.2
  Top 0.41: 89.25,21.25 Q5.4 Q5.2 89.38,6.13 88.62,5.5 X5.2
N$116
  Top 0.152: LED5.C 79.5,5.38 81.5,5.38 X4.2
  Top 0.41: Q4.4 82.38,21.25 82.38,15.13 Q4.2 82.38,14.88 82.38,6.13 81.62,5.38 X4.2
N$117
  Top 0.254: LED6.A 86.38,3.88 86.38,2.38 R20.1
N$118
  Top 0.254: R21.1 LED7.A
N$127
  Top 0.152: LED3.A 12.25,21.75 12.38,21.63 R15.1
N$128
  Top 0.152: C51.1 84.88,46.63 83.25,46.63 U6.10
N$129
  Top 0.254: LED1.A 11.88,53.25 R14.1
N$130
  Top 0.152: LED2.A 11.75,35.88 11.88,35.75 R16.1
N$133
  Top 0.254: Q3.4 14.38,28.13 14.38,28.63 14.38,29.5 R32.1
N$147
  Top 0.152: 96.88,54.63 R24.1 95.25,54.63 U18.1 95.12,54.63 95.12,53.38 94,52.25 S2.3
N$148
  Top 0.152: R23.1 95.25,55.88 U18.2 95.12,55.88 94.75,55.88 91.38,52.5 91.38,52.25 S2.4
N$149
  Top 0.152: R22.1 95.25,57.25 U18.3
N$233
  Top 0.254: U10.7 67.62,50.88 68,50.5 69.12,50.5 R43.1 69.25,50.5 69.75,50.5 | 69.75,50.5 69.75,50.63 | 69.75,50.5 70.5,50.5 R42.2
N$234
  Top 0.152: LED3.C 10.75,24.5 Q3.TH 9.5,24.13 9.5,23.13 R55.1 | C59.1 12.88,29.5 10.75,29.5 D1.A | Q3.8 8.62,24.25 8.62,24.38
  Top 0.254: 9.88,24.5 9.88,25 | 8.5,26.12 8.5,26.75 Q3.6 | 8.5,26.12 8.5,25.5 Q3.7 | 8.5,26.63 9.88,26.75 9.88,28.13 | 8.5,27.88 8.5,28 Q3.5 | 9.88,26.38 Q3.TH 9.62,25.63 8.62,25.63
  Top 0.813: 8.5,27.88 8.5,26.63 | 8.62,24.38 8.62,25.63
  Top 2: D1.A 9.88,28.13 9.88,28 9.88,26.75 9.88,26.38 | 9.88,26.38 9.88,25.5 9.88,25 | 8.5,26.12 9.62,26.13 9.88,26.38
  Top 2.54: X3.2 8.5,26.12
N$237
  Top 0.152: C14.1 23,61.25 21.88,61.25 R38.1 21.75,61.25 21.75,64 X9.1 21.88,64.13 24.62,66.88 29.12,66.88 R13.1
N$238
  Top 0.305: C55.2 58.62,51.88 58.62,51.75 57.5,51.75 56.5,50.75 56.5,47.63 D4.C | 62,50.25 U10.5 | 62,48 L2.P$2
  Top 0.406: 62,48 62,50.25
  Top 0.813: 62.12,47.63 60.5,47.63
  Top 0.819: 60.5,47.63 60.12,47.25 56,47.25 D4.C | 62.12,47.63 L2.P$2
N$239
  Top 0.152: U6.8 82.38,45.38 82.38,43.63 82.25,43.5 R41.1
N$240
  Top 0.152: C16.1 39.12,64.25 | R18.1 48.38,67.13 43.5,67.13 40.62,64.25 X7.1 40.5,64.25 39.12,64.25 | 39.12,64.25 R40.1
N$241
  Top 0.152: C15.1 29.62,65.25 29.62,64.13 R39.1 29.75,64.13 31.12,64.13 X8.1 31.25,64.13 34.12,67 38.38,67 R17.1
N$242
  Top 0.152: R56.1 8.75,38.25 8.75,39.5 Q1.8
  Top 0.254: 9.62,39.75 9.62,40.38 9.62,41 | LED2.C 10.25,38.13 | 10.25,38.13 10.25,39.13 10.25,39.63 8.38,39.63 Q1.8 8.5,39.75 9,41 | 10.25,38.13 C58.1 | 8.5,42.25 8.25,42.25 9,42.25 9,41 | 8.5,42.25 Q1.6 | Q1.TH 9.88,41.63 | 8.5,43.25 8.62,43.5 Q1.5 | 8.5,42.63 8.5,42.25 | 8.5,42.25 9.88,42.25 | 9,41 8.5,40.88 Q1.7
  Top 0.813: 8.5,43.25 8.5,42.63
  Top 2: D2.A 9.88,42.25 9.88,41.63 9.88,41.13 9.62,41
  Top 2.54: X20.3 4.12,43.51 4.12,41 | 4.12,41 4.5,41 4.12,41 | 4.12,41 4.12,38.43 X20.4 | 9.62,41 9,41
  Top 3: 9,41 4.5,41
N$243
  Top 0.254: C54.1 66.75,53.88 66.75,52.38 U10.10
N$244
  Top 0.254: U10.8 66.88,51.38 68.38,51.38 68.75,51.75 68.75,52 C56.1
N$245
  Top 0.305: C55.1 U10.2
N$246
  Top 0.254: 70,52.63 70,52 C56.2 | 70,52.63 70.12,52.63 | 70,52.63 70,53.38 R44.1
SER_2
  Top 0.152: U1.9 26.88,37.38 33,37.38 34,38.38 35.12,38.38 35.5,38 35.5,37.38 U2.14
SER_3
  Top 0.152: U2.9 38.88,37.38 39.88,38.38 47.12,38.38 47.5,38 47.5,37.38 U3.14
SER_4
  Top 0.152: U3.9 50.88,37.38 51.88,38.38 59.12,38.38 59.5,38 59.5,37.38 U4.14
SER_5
  Top 0.152: U4.9 62.88,37.38 62.75,37.5 63.62,38.38 68.5,38.38 70.12,40 70.88,40 71.5,39.38 71.5,37.38 U5.14
SPI1_CS0
  Top 0.152: U12.15 39,52 39,52.38 42.88,56.25 51.75,56.25 53.12,57.63 53.21,57.66 53.25,57.63 P9.28
SPI1_CS1  (via drill 0.3)
  Top 0.152: 60.88,35.25 60.88,37.25 U4.12 | v69.5,35.38 69.38,35.25 60.88,35.25 | v71,35.38 71.5,35.38 72.75,36.63 72.75,37.25 U5.12 | v36.88,38.5 36.88,37.38 U2.12 | v38.5,38.5 38.75,38.75 48,38.75 48.75,38 48.75,37.38 U3.12 48.88,37.25 48.88,36.63 50.25,35.25 v57.12,35.25 | v58.88,35.25 60.88,35.25 | v25.38,38.5 24.88,38 24.88,37.38 U1.12
  Bottom 0.152: v71,35.38 v69.5,35.38 | v38.5,38.5 37,38.5 v36.88,38.5 | 35.5,57.63 35.5,39.88 v36.88,38.5 | 35.5,57.63 35.43,57.66 | v57.12,35.25 v58.88,35.25 | v36.88,38.5 v25.38,38.5 | 35.5,57.63 P9.42
SPI1_MISO  (via drill 0.3)
  Top 0.152: v39,45 39,46 U12.2
  Bottom 0.152: v39,45 49.5,55.5 49.5,59 50.62,60.13 50.67,60.2 50.62,60.25 50.75,60.25 P9.29
SPI1_MOSI  (via drill 0.3)
  Top 0.152: v39,44.13 38.38,44.75 38.38,46 U12.1 | v38.5,39.88 37.75,39.88 37.5,39.63 36.62,39.63 36.5,39.75 24.62,39.75 23.62,38.75 23.62,37.38 U1.14
  Bottom 0.152: 50.62,57.63 50.62,55.75 v39,44.13 38.5,43.63 v38.5,39.88 | 50.62,57.63 50.67,57.66 | 50.62,57.63 50.75,57.63 P9.30
SPI1_SCLK  (via drill 0.3)
  Top 0.152: 49.5,38.75 49.5,37.38 U3.11 | 49.5,38.75 49.12,39.13 v37.88,39.13 37.5,38.75 37.5,37.38 U2.11 37.38,37.25 37.38,36.5 36.88,36 v36,36 | 61.5,38.75 61.5,37.38 U4.11 61.5,38.75 | 49.5,38.75 61.5,38.75 | 73.5,37.38 73.38,37.38 U5.11 73.5,37.38 | 61.5,38.75 68.38,38.75 70,40.38 72.38,40.38 73.5,39.25 73.5,37.38 | v37.62,51.88 38.25,51.88 U12.16 38.38,52 38.38,52.38 42.62,56.63 46,56.63 47,57.63 47,59 48.12,60.13 48.13,60.2 48.12,60.25 P9.31 | 25.5,37.25 U1.11 25.5,37.25 | v25.5,36 25.5,37.25
  Bottom 0.152: v37.62,51.88 37,51.88 36.75,51.5 36.75,41.5 37.88,40.25 v37.88,39.13 | v25.5,36 29.25,36 29.5,36.25 35.75,36.25 v36,36
STEP1_EXT1  (via drill 0.6)
  Top 0.41: X17.4 56.5,5.25 56.5,5.5 59.5,8.5 59.5,12.5 v58.5,13.5 | U16.5 59.5,19.63 58.5,18.63 v58.5,15.88
  Bottom 0.41: v58.5,13.5 v58.5,15.88
STEP1_EXT2  (via drill 0.6)
  Top 0.41: U17.5 71.5,19.63 70.5,18.63 v70.5,15.88
  Bottom 0.41: X18.4 67.75,5.38 67.25,5.88 67.25,12.38 70.5,15.63 v70.5,15.88
STEP1_X  (via drill 0.6)
  Top 0.41: U13.5 23.5,19.88 22.88,19.25 v22.88,15.88
  Bottom 0.41: v22.88,15.88 23.75,15 23.75,6.88 22.12,5.25 X14.4
STEP1_Y  (via drill 0.6)
  Top 0.41: U14.5 35.5,19.75 34.62,18.88 v34.62,17.38
  Bottom 0.41: X15.4 33.75,5.38 34.12,5.75 34.12,12.63 34.62,13.13 v34.62,17.38
STEP1_Z  (via drill 0.6)
  Top 0.41: v46.88,13.63 46.88,8.88 45.12,7.13 45.12,5.25 X16.4 | U15.5 47.5,19.75 46.88,19.13 v46.88,16.75
  Bottom 0.41: v46.88,13.63 v46.88,16.75
STEP2_EXT1  (via drill 0.6)
  Top 0.41: v60.62,18.63 60.75,18.75 60.75,21.75 U16.7
  Bottom 0.41: v60.62,18.63 60.62,15.5 62.25,13.88 62.25,8.63 61.5,7.88 61,7.88 59,5.88 59,5.25 X17.3
STEP2_EXT2  (via drill 0.6)
  Top 0.41: v72,18 72.75,18.75 72.75,21.75 U17.7
  Bottom 0.41: v72,18 72,14.63 69.75,12.38 69.75,6 70.38,5.38 X18.3
STEP2_X  (via drill 0.6)
  Top 0.41: U13.7 24.75,21.75 24.75,18.88 v24.38,18.5
  Bottom 0.41: v24.38,18.5 24.38,5.63 24.75,5.25 X14.3
STEP2_Y  (via drill 0.6)
  Top 0.41: U14.7 36.75,21.75 36.75,18.75 v36.38,18.38
  Bottom 0.41: v36.38,18.38 36.38,17.63 36.75,17.25 36.75,5.88 36.25,5.38 X15.3
STEP2_Z  (via drill 0.6)
  Top 0.41: U15.7 48.75,21.75 48.75,18.75 v48.62,18.63
  Bottom 0.41: v48.62,18.63 48.62,14.13 46.88,12.38 46.88,5.88 47.5,5.25 X16.3
STEP3_EXT1  (via drill 0.6)
  Top 0.41: U16.10 62.75,18.88 64,17.63 v64,15.88 | X17.2 61.5,5.38 61.5,7.88 62.25,8.63 62.25,12.5 63.5,13.75 v64.5,13.75
  Bottom 0.41: v64,15.88 64,14.25 v64.5,13.75
STEP3_EXT2  (via drill 0.6)
  Top 0.41: U17.10 74.75,18.25 v75,18
  Bottom 0.41: v75,18 75,12.5 74.75,12.25 74.75,7.13 73,5.38 X18.2
STEP3_X  (via drill 0.6)
  Top 0.41: U13.10 26.75,19.25 28,18 v28,15.88
  Bottom 0.41: v28,15.88 28,5.88 27.25,5.25 X14.2
STEP3_Y  (via drill 0.6)
  Top 0.41: U14.10 38.75,19.13 39.88,18 v39.88,17.88 | v39.88,13.25 39.25,12.63 39.25,5.75 38.75,5.25 X15.2
  Bottom 0.41: v39.88,13.25 v39.88,17.88
STEP3_Z  (via drill 0.6)
  Top 0.41: U15.10 50.75,19.13 v51.88,18
  Bottom 0.41: v51.88,18 51.88,8.5 50.12,6.75 X16.2
STEP4_EXT1  (via drill 0.6)
  Top 0.41: v61.5,18 61.5,21.75 U16.8
  Bottom 0.41: v61.5,18 61.5,15.5 64.75,12.25 64.75,5.88 64.12,5.25 X17.1
STEP4_EXT2  (via drill 0.6)
  Top 0.41: v73.25,18 73.5,18.25 73.5,21.75 U17.8 | v73.62,7.38 75.5,5.5 75.5,5.25 X18.1
  Bottom 0.41: v73.25,18 73.25,13.25 72.38,12.38 72.38,8.63 v73.62,7.38
STEP4_X  (via drill 0.6)
  Top 0.41: v25.5,18 25.5,21.75 U13.8
  Bottom 0.41: X14.1 29.75,5.38 28.88,6.25 28.88,16.5 28.12,17.25 26.25,17.25 v25.5,18
STEP4_Y  (via drill 0.6)
  Top 0.41: U14.8 37.5,21.75 v37.5,18
  Bottom 0.41: v37.5,18 37.5,14.13 39.25,12.38 39.25,7.75 41.25,5.75 X15.1
STEP4_Z  (via drill 0.6)
  Top 0.41: U15.8 49.5,21.75 v49.5,18 | v49.5,13.5 49.5,8.88 52.62,5.75 52.62,5.25 X16.1
  Bottom 0.41: v49.5,13.5 v49.5,18
STEP_EXT1  (via drill 0.3)
  Top 0.152: v60.12,30 60.75,29.38 60.75,28 U16.22 | v71.12,55.25 73.5,57.63 P9.12
  Bottom 0.152: v60.12,30 60.12,43.75 59,44.88 59,49.38 61,51.38 67.25,51.38 v71.12,55.25 71.25,55.38
STEP_EXT2  (via drill 0.3)
  Top 0.152: v72.88,26.88 72.88,27.88 U17.22 | v77.25,19 77.25,15.63 73.62,12 P8.11
  Bottom 0.152: v72.88,26.88 75.38,26.88 76,26.25 76,24.5 77.25,23.25 v77.25,19
STEP_X  (via drill 0.3)
  Top 0.152: v24.75,29 24.75,28 U13.22 | v53.62,25.75 53.62,24.25 54.38,23.5 54.38,19.38 v54.5,19.25
  Bottom 0.152: v24.75,29 30.25,29 31.88,27.38 40.75,27.38 41,27.13 51.88,27.13 | v53.62,25.75 53.25,25.75 51.88,27.13 | 51.88,27.13 52.25,27.13 | v54.5,19.25 54.75,19 60,19 60.38,19.38 61.62,19.38 65.38,15.63 65.38,12.5 65.88,12 65.91,11.94 65.88,11.88 P8.17
STEP_Y  (via drill 0.3)
  Top 0.152: v36.75,29 36.75,28 U14.22 | v54.38,33.13 55.12,33.88 v62.75,33.88 | v78.62,19 78.62,15.25 77.38,14 77.38,11.5 76.5,10.63 74.88,10.63 73.75,9.5 73.62,9.38 P8.12
  Bottom 0.152: v36.75,29 50.25,29 v54.38,33.13 | v62.75,33.88 69,33.88 73.5,29.5 74.5,29.5 77,27 77,24.63 78.62,23 v78.62,19
STEP_Z  (via drill 0.3)
  Top 0.152: v42.38,18.38 42.38,21.38 42.5,21.5 43.75,21.5 44,21.75 44,24.38 46.25,26.63 47.88,26.63 48.75,27.5 48.75,27.88 U15.22 | v43.5,5.5 43.5,4.13 45.12,2.5 63.38,2.5 65.38,4.5 65.38,7.25 67.25,9.13 67.25,9.75 68.5,10.88 69.62,10.88 70.62,11.88 71,11.88 P8.13
  Bottom 0.152: v42.38,18.38 41.75,17.75 41.75,7.25 v43.5,5.5
SW
  Top 0.152: C51.2 85,47.75 83.25,47.75 U6.12 U6.13 82.5,48.5 | U6.1 80.25,47.75 80.88,48.38 U6.16
  Top 0.406: 82.5,48.5 82.5,50.75 82,50.75 L1.1 81.88,50.75 81.12,50.75 80.88,50.63 80.88,48.38
SYS_5V  (via drill 0.5)
  Top 0.254: R54.2 96.9,68.88 | R53.2 91.88,68.88 | R52.2 85.5,68.88 | 79.12,68.88 R51.2 | 72.88,67.25 R50.2 72.75,68.88 | 66.38,68.88 R49.2
  Top 0.305: X12.1 51.75,64.25 53.62,66.13 59.75,66.13 62.5,68.88 66.38,68.88 72.75,68.88 v78.75,68.88 79.12,68.88 85.5,68.88 91.88,68.88 96.9,68.88
  Bottom 0.152: 78.75,57.75 P9.8 | 78.75,60.38 P9.7
  Bottom 0.305: v78.75,68.88 78.75,60.38 78.62,60.25 78.61,60.2 78.75,60.13 78.75,57.75 78.61,57.66
TERM_EXT1  (via drill 0.3)
  Top 0.152: R38.2 21.88,59.88 22.5,59.25 23.75,59.25 24.38,59.88 C26.1 24.5,59.88 29.25,59.88 30,59.13 v39.25,59.13
  Bottom 0.152: v39.25,59.13 44.5,59.13 45.5,60.13 45.59,60.2 45.62,60.25 P9.33
TERM_EXT2
  Top 0.152: R40.2 37.88,63.88 37.88,62.75 C46.1 37.88,62.63 39,61.5 41,61.5 41.88,60.63 41.88,58.88 43,57.75 | 43,57.75 43.05,57.66 | 43,57.75 43.12,57.75 P9.36
TERM_HBP  (via drill 0.3)
  Top 0.152: C45.1 28.38,62.75 28.38,64 R39.2 28.5,64.13 28.5,64.38 29,64.88 29,65.88 29.38,66.25 32.88,66.25 34.25,67.63 v35.5,67.63
  Bottom 0.152: v35.5,67.63 39.25,63.88 39.25,63.25 42.25,60.25 43,60.25 | 43,60.25 43.05,60.2 | 43,60.25 43.12,60.25 P9.35
VDD_5V  (via drill 0.3)
  Top 0.152: 5V.TP 81,40.75 81,43.38 R41.2 81,43.5 v81,44.5 81,45.38 U6.5 80.88,45.5 | P9.6 81.25,57.75 81.25,57.63
  Top 0.406: C49.1 C50.1 77.62,54.38 82,54.38 L1.2 81.25,54.5 81.25,57.63 81.15,57.66
  Bottom 0.152: 81,57.63 81.15,57.66 81,57.63 | 81,57.63 v81,44.5 | P9.6 81.25,57.75 81.13,57.72 | 81.25,60.13 P9.5
  Bottom 0.406: 81.28,60.2 81.25,60.13 81.25,57.75 81.13,57.72 81.15,57.66
VDD_12V  (via drill 0.5, 0.7)
  Top 0.152: 70.62,42.25 12V.TP | 61.88,41.38 L2.P$1 | 17.38,33.25 U9.2
  Top 0.254: 12V.TP R42.1 | 17.38,64.25 17.38,63 C25.1 17.38,62.88 17.38,54.13 17.38,52.38 18,51.75 18,48.5 | 17.38,64.25 C24.1 | 17.38,64.25 C24.1 | C24.1 17.38,64.75 18,65.38 18,65.75 18,65.88 18,66 18,66.63 17.88,66.75 16.88,66.75 U7.2 | 17.38,64.25 C24.1 | 18.38,33.25 18.25,33.25 17.5,33.25 U9.2 | 18.38,33.25 18.38,31.88 18.25,31.75 17.38,31 17.38,30.88 C22.1 17.38,30.75 17.38,30.13 17.38,29.63 C23.1 | 18.38,33.25 18.38,33.75 19.25,34.63 v19.25,41 17.38,42.88 17.38,44.88 C21.1 17.38,45 17.38,45.5 17.38,46.13 C20.1 17.38,46.25 17.38,46.63 17.88,46.63 18,46.75 18,48.5 | 18,48.5 16.88,48.5 U8.2
  Top 0.305: 17.38,33.25 17.25,33.25 17.25,33.38
  Top 0.406: v26.5,41 60,41 60.62,41.63 61.88,41.63 L2.P$1
  Top 0.813: 84.12,1.13 R20.2 | 91,1.13 R21.2 | v79.62,35.13 73.12,41.63 12V.TP
  Top 0.819: R21.2 97.88,1.13 97.88,5.25 X6.1 | X4.1 84.12,5.25 84.12,1.13 R19.2 | R20.2 91,1.13 91,2.38 X5.1 | L2.P$1 62.25,41.63 67.62,41.63 C53.1 68.12,41.63 12V.TP
  Bottom 0.406: v26.5,41 v19.25,41
  Bottom 0.813: X5.1 91.02,15.13 90.62,15.5 86,20.13 86,28.75 v79.62,35.13
VDD_ADC  (via drill 0.3)
  Top 0.152: 38.25,68.25 38.38,68.38 R17.2 38.5,68.25 | 29.12,68.25 R13.2 | 48.38,68.25 R18.2
  Top 0.254: 38.25,68.25 29.12,68.25 | 38.5,68.25 47,68.25 | 47,68.25 48.38,68.25 | 47,68.25 v47,67.75
  Bottom 0.152: P9.32 48.25,57.75 48.12,57.75
  Bottom 0.254: v47,67.75 47,58.88 48.12,57.75 48.13,57.66
VDD_IN  (via drill 0.3, 0.6, 0.7)
  Top 0.152: U6.3 80.25,46.75 80.25,47.13 U6.2 | 54.62,25.63 C35.1 | 55.75,25.63 C42.1 | 30.62,25.63 C27.1 | 31.75,25.63 C31.1 | 66.62,25.63 C29.1 | 67.75,25.63 C43.1 | 18.75,18.13 C12.+ | 67.12,22.5 C28.1 | 55.12,22.25 C34.1 | C4.1 31,18.13 30.62,17.75 29.75,17.75 27.5,20 v27.62,20.13 | v46.62,20.13 46.25,19.75 46.25,17.5 45.62,16.88 44.62,16.88 43.88,17.63 C6.1 | 51.75,19.88 v51.62,20 | C8.1 55.38,18.13 56.12,17.38 57.12,17.38 58,18.25 58,19.88 58.5,20.38 v58.62,20.5
  Top 0.154: 86.12,47.13 95.62,47.13 96.88,45.88 96.88,44.25 R11.2 | 83.25,47.25 U6.11
  Top 0.254: 83.25,47.25 83.75,47.25 83.88,47.13 86.12,47.13 86.12,44.25 81,39.13 | C10.1 67.38,18.13 67.38,17.25 67.5,17.13 68.88,17.13 69.5,17.75 69.5,17.88 v69.62,18 | C2.1 17.75,19.5 17.38,17.88 19,17.88 C12.+
  Top 0.305: 60.25,50 61.12,50.88 U10.4 | 77.75,46.93 77.75,47.13 C47.1 77.75,46.63 | 80.12,46.93 U6.3 | 77.75,45 C48.1 77.75,44.88
  Top 0.4: 17.12,18 C12.+ 17.12,17.75 | R45.1 14.12,8.13 14.12,18
  Top 0.406: 39.38,21.88 U14.11 | 60.38,49.88 60.25,50 | v21.88,20.13 22.88,21.13 22.88,21.75 U13.4
  Top 0.41: v39.62,20.13 39.38,20.38 39.38,21.75 U14.11 | v51.62,20 51.38,20.25 51.38,21.75 U15.11 | v27.62,20.13 27.38,20.38 27.38,21.75 U13.11 | v63.62,20 63.38,20.25 63.38,21.75 U16.11 | U17.11 75.38,21.75 75.38,20.63 v75.88,20.13 | v70.62,20.13 70.88,20.38 70.88,21.75 U17.4 | v58.62,20.5 58.88,20.75 58.88,21.75 U16.4 | v46.62,20.13 46.88,20.38 46.88,21.75 U15.4 | v34.5,20.13 34.88,20.5 34.88,21.75 U14.4 | 67.12,22.88 C28.1
  Top 0.813: 55.75,25.63 55.12,25.63 | 55.12,25.63 54.62,25.63 | 55.12,25.63 v55.12,23.88 C34.1 | 31.75,25.63 31.12,25.63 | 31.12,25.63 v31.12,24 C30.1 | 31.12,25.63 30.62,25.63 | 60.25,50 C52.1 | 81,39.13 12..24V.TP | 12..24V.TP 81,31.5 79.25,29.75 C18.1 | 77.75,46.93 80.12,46.93 | 77.75,45 77.75,46.63 | 12..24V.TP 79.38,39 v77.75,40.63 77.75,44.75 C48.1 | 60.38,49.88 v60.88,49.38
  Top 0.819: C18.1 79.12,27.88 79.12,26.88 C19.1 79.12,26.25 C44.1 79.1,25.03 79.12,25 79.12,21.38 77.88,20.13 v75.88,20.13 | C38.1 43.12,25.6 | 43.12,25.6 C33.1 | C32.1 v43.12,24.13 43.12,25.6 | 67.75,25.63 67.12,25.63 | 67.12,25.63 66.62,25.63 | 67.12,25.63 v67.12,24 67.12,22.88
  Top 1.422: 17.12,17.75 19.5,17.75 v21.88,20.13
  Top 2: F1.4 F1.3 13.12,18 14.12,18 17.12,18
  Bottom 0.254: 69.62,20.13 v69.62,18
  Bottom 0.41: v51.62,20 51.62,20.13 | v58.62,20.5 58.62,20.38
  Bottom 0.813: 43.12,20.13 v43.12,24.13 | v60.88,49.38 69,49.38 v77.75,40.63
  Bottom 0.819: 51.75,20.13 51.62,20.13
  Bottom 1.422: v75.88,20.13 v70.62,20.13 69.62,20.13 67.12,20.13 | 67.12,20.13 63.62,20.13 v63.62,20 62.62,21 58.75,21 58.75,20.38 58.62,20.38 58.62,21 55.12,21 | 55.12,21 52.62,21 51.75,20.13 | 51.62,20.13 v46.62,20.13 43.12,20.13 v39.62,20.13 v34.5,20.13 31.12,20.13 | 31.12,20.13 v27.62,20.13 v21.88,20.13 | 67.12,20.13 v67.12,24 | 31.12,20.13 v31.12,24 | 55.12,21 v55.12,23.88
  pour Top (isolate 0.5): 13.38,11.5 0,11.5 0,69.5 11.38,69.5 10.88,21.75 13.38,21.75
  pour Bottom (isolate 0.5): 13,69.5 13,15.38 7,15.38 7,20.75 0,20.75 0,69.5
VIN
  Top 0.254: 13.38,6.5 LED8.A
  Top 1.27: 4.5,5.63 4,5.25
  Top 2: X2.3 4,5.25 X2.4 | F1.2 F1.1 4.5,5.63
  pour Top: 0,10.5 13.38,10.5 13.38,0 0,0
VREF_EXT1  (via drill 0.3)
  Top 0.152: v60.75,43 59.75,44 43.25,44 41.62,45.63 41.62,46 U12.6 | v58.75,26.88 58.38,26.5 58.38,23.25 59,22.63 63.88,22.63 64.38,22.13 | 64.38,22.13 64.62,21.88 U16.13 | 64.38,22.13 64.12,21.88 U16.12
  Bottom 0.152: v60.75,43 60.75,28.88 v58.75,26.88
VREF_EXT2  (via drill 0.3)
  Top 0.152: v47.5,51 44.62,53.88 41.25,53.88 39.62,52.25 39.62,52 U12.14 | v54.88,40.25 69.38,40.25 69.88,40.75 72.62,40.75 78.38,35 78.38,23.5
  Top 0.154: 76.75,20.88 76.75,21.75 U17.13 | 76.75,20.88 76.12,20.88 76,21 76,21.75 U17.12 | 76.75,20.88 77.5,20.88 78.38,21.75 78.38,23.5
  Bottom 0.152: v47.5,51 54.88,43.63 v54.88,40.25
VREF_X  (via drill 0.3)
  Top 0.152: v39.62,43.38 39.62,46 U12.3 | 29.88,25.75 29.88,25.88 29.88,28.38 | U13.12 28.12,21.88 28.62,21.88 U13.13
  Top 0.154: U13.13 28.75,21.88 v28.75,23.25 | 29.88,25.88 v29.62,25.63 | 29.88,28.38 29.88,29 v31.62,30.75
  Bottom 0.152: v39.62,43.38 39.62,38.75 v31.62,30.75
  Bottom 0.154: v29.62,25.63 29.62,24.13 v28.75,23.25
VREF_Y  (via drill 0.3)
  Top 0.152: U12.4 40.25,44.63 v42.25,42.63 | v42.25,33.75 42.25,27.75 40.75,26.25 40.75,21.88 U14.13 40.62,21.75 40.12,21.75 U14.12
  Bottom 0.152: v42.25,33.75 v42.25,42.63
VREF_Z  (via drill 0.3)
  Top 0.152: v43.25,43.25 40.88,45.63 40.88,46 U12.5 | v52.62,33.88 53.88,32.63 53.88,26.88 53,26 53,23.63 52.62,23.25 52.62,21.88 U15.13 52.62,21.75 52.12,21.75 U15.12
  Bottom 0.152: v52.62,33.88 v43.25,43.25
X_DECAY
  Top 0.152: U13.19 26.75,28.88 24.88,30.75 24.88,31.38 U1.5
X_MODE0
  Top 0.152: U13.24 23.5,31.38 U1.3
X_MODE1
  Top 0.152: U13.25 22.88,28 22.88,31.38 U1.2
X_MODE2
  Top 0.152: U13.26 22.25,28 22.25,31.38 U1.1
X_NENABLE
  Top 0.152: U13.21 25.38,28 25.38,29.63 24.25,30.75 24.25,31.38 U1.4
X_NRESET
  Top 0.152: U13.16 28.62,28 28.62,28.5 26.75,30.38 26.62,30.38 26.25,30.75 26.25,31.38 U1.7
X_NSLEEP
  Top 0.152: U13.17 28,28 28,28.38 26,30.38 25.88,30.38 25.5,30.75 25.5,31.38 U1.6
Y_DECAY
  Top 0.152: U14.19 38.75,28.88 36.88,30.75 36.88,31.38 U2.5
Y_MODE0
  Top 0.152: U14.24 35.5,31.38 U2.3
Y_MODE1
  Top 0.152: U14.25 34.88,28 34.88,31.38 U2.2
Y_MODE2
  Top 0.152: U14.26 34.25,28 34.25,31.38 U2.1
Y_NENABLE
  Top 0.152: U14.21 37.38,28 37.38,29.63 36.25,30.75 36.25,31.38 U2.4
Y_NRESET
  Top 0.152: U14.16 40.62,28 40.62,28.5 38.75,30.38 38.62,30.38 38.25,30.75 38.25,31.38 U2.7
Y_NSLEEP
  Top 0.152: U14.17 40,28 40,28.38 38,30.38 37.88,30.38 37.5,30.75 37.5,31.38 U2.6
Z_DECAY
  Top 0.152: U15.19 50.75,28.88 48.88,30.75 48.88,31.38 U3.5
Z_MODE0
  Top 0.152: U15.24 47.5,31.38 U3.3
Z_MODE1
  Top 0.152: U15.25 46.88,28 46.88,31.38 U3.2
Z_MODE2
  Top 0.152: U15.26 46.25,28 46.25,31.38 U3.1
Z_NENABLE
  Top 0.152: U15.21 49.38,28 49.38,29.63 48.25,30.75 48.25,31.38 U3.4
Z_NRESET
  Top 0.152: U15.16 52.62,28 52.62,28.5 50.75,30.38 50.62,30.38 50.25,30.75 50.25,31.38 U3.7
Z_NSLEEP
  Top 0.152: U15.17 52,28 52,28.38 50,30.38 49.88,30.38 49.5,30.75 49.5,31.38 U3.6

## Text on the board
tNames: HBP | Ext2 | X1 | Y1 | Z1 | X2 | Y2 | Z2 | Ext1 | Thermistors | Dallas W1 | End stops | Ext2 | Power | Heaters | Replicape | HBP | Rev A4 | Ext1 | Z | Ext1 | Fans | X | Y | Ext2 | A | B | C | 12..24V
tDocu: Fuse | 20A | Steppers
